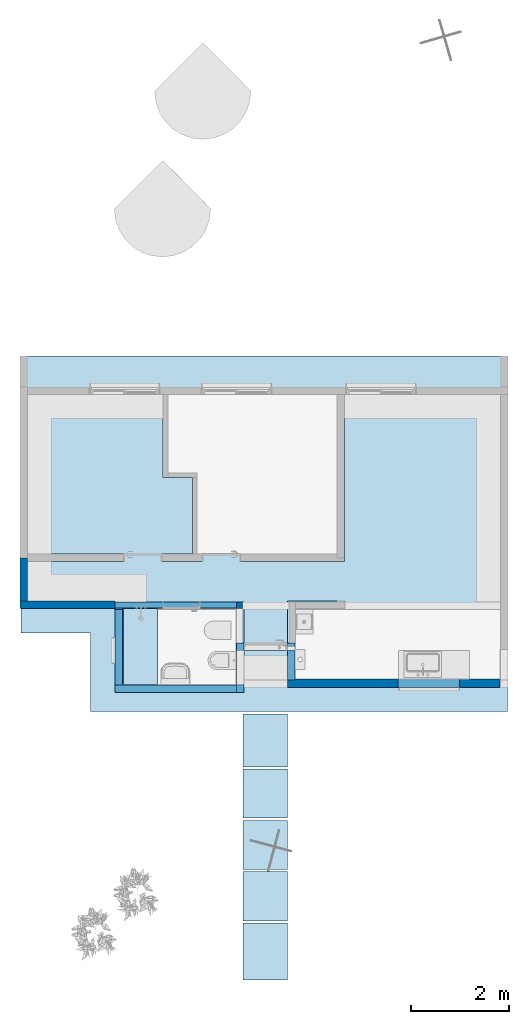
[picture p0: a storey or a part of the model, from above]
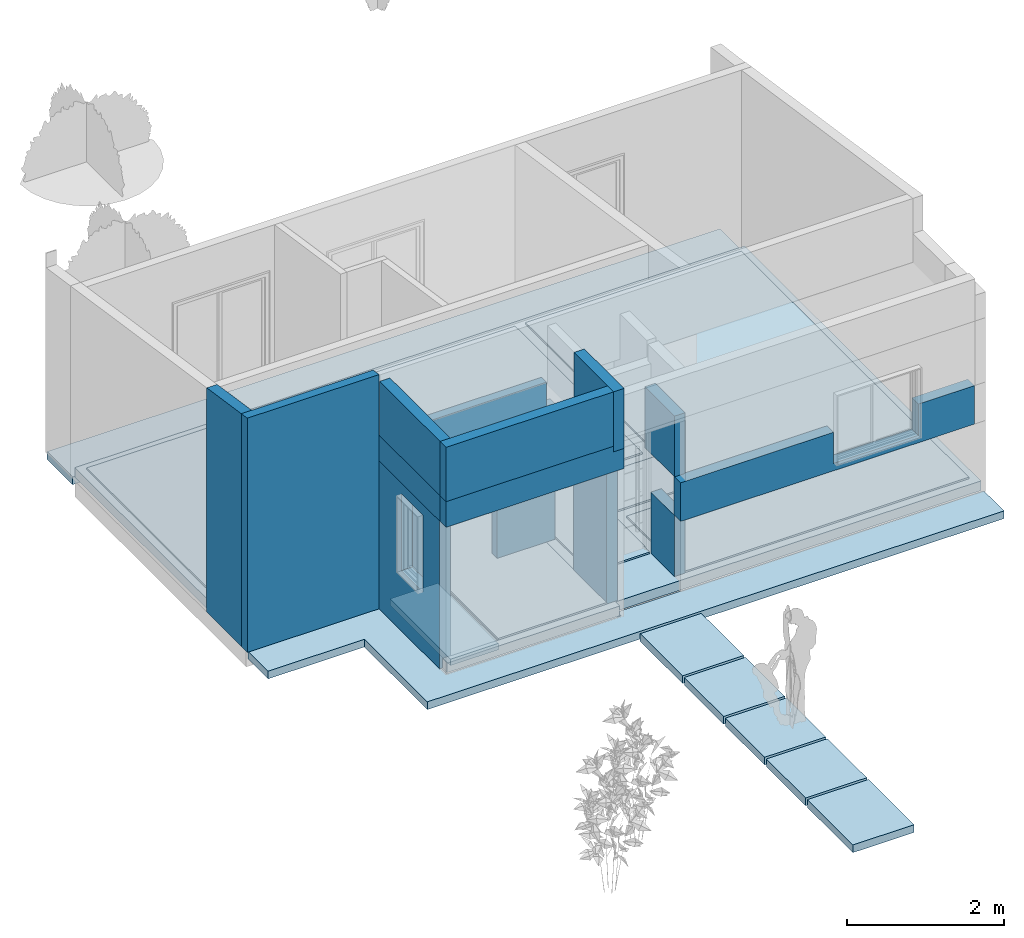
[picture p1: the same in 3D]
Properties of the parts of a building model (IFC2X3)

# File
Description: ViewDefinition [CoordinationView_V2.0]
File name: Project Number
Time: 2021-10-06T08:28:48
Written by: The EXPRESS Data Manager Version 5.02.0100.07 : 28 Aug 2013
Made in: 20200210_1400(x64) - Exporter 20.2.12.1 - Alternate UI 20.2.12.1
Comment: STEP Physical File produced by: The EXPRESS Data Manager Version 5.02.0100.07 : 28 Aug 2013 * Module: EDMstepFileFactory/EDMstandAlone * Creation date: Wed Oct 06 08:28:48 2021 * Host: d-417 * Database: C:\Users\msoler\AppData\Local\Temp\b61d57f0-5f59-4d53-9b33-197beb0c06ca\71092de3-7ad1-4322-8656-2e5e5e605928\ifc * Database version: 5507 * Database creation date: Wed Oct 06 08:28:41 2021 * Schema: IFC2X3 * Model: DataRepository.ifc * Model creation date: Wed Oct 06 08:28:42 2021 * Header model: DataRepository.ifc_HeaderModel * Header model creation date: Wed Oct 06 08:28:42 2021 * EDMuser: sdai-user * EDMgroup: sdai-group * License ID and type: 5605 : Permanent license. Expiry date: * EDMstepFileFactory options: 020000

# IfcProject, Project Number
LongName: Project Name; Phase: Project Status

# IfcSite, Surface:604594
RefLatitude: 42, 21, 31, 181945; RefLongitude: -71, -3, -24, -263305; RefElevation: 0 m
Pset_ProductRequirements - Category: Topography

# IfcBuilding
Pset_BuildingCommon - NumberOfStoreys: 2
Pset_ProductRequirements - Category: Project Information

# IfcBuildingStorey: Level:8mm Head (2)
Pset_ProductRequirements - Category: Levels
Name | LongName = Pset_AirSideSystemInformation, Name = Pset_ProductRequirements, Name | Elevation (m)
Nivel 0.0 | Nivel 0.0 | 0
Nivel 1 | Nivel 1 | 2.7

# IfcSpace (6)
In: Nivel 0.0
InteriorOrExteriorSpace: INTERNAL
Pset_ProductRequirements - Category: Rooms
Pset_SpaceCommon - Category: Rooms; FloorCovering: Cerámico; CeilingCovering: Placa yeso suspendido
Name | LongName = Pset_AirSideSystemInformation, Name = Pset_ProductRequirements, Name | Reference
1 | Hall distribuidor y paso | Hall distribuidor y paso 1
2 | Estar comedor | Estar comedor 2
4 | Dormitorio 1 | Dormitorio 1 4
5 | Dormitorio 2 | Dormitorio 2 5
6 | Baño | Baño 6 | Pset_SpaceCommon - WallCovering: cerámico
3 | Lavadero | Lavadero 3 | Pset_SpaceCommon - WallCovering: cerámico

# IfcBuildingElementProxy: Barberry - 1.0 Meters (3)
In: Nivel 0.0
Type - Pset_BuildingElementProxyCommon - Reference: Barberry - 1.0 Meters
Type - Pset_ProductRequirements - Category: Planting
Type - Pset_QuantityTakeOff - Reference: Barberry - 1.0 Meters
Pset_BuildingElementProxyCommon - sets with these values: 2
Name (M_RPC Shrub:Barberry - 1.0 Meters:...)
617424
617426
707226

# IfcBuildingElementProxy: Enscape AssetDefinition - Bamboo 5 (2)
In: Nivel 0.0
Type - Pset_BuildingElementProxyCommon - Reference: Enscape AssetDefinition - Bamboo 5
Type - Pset_ProductRequirements - Category: Planting
Type - Pset_QuantityTakeOff - Reference: Enscape AssetDefinition - Bamboo 5
Pset_BuildingElementProxyCommon - sets with these values: 2
Name (Bamboo:Enscape AssetDefinition - Bamboo 5:...)
669530
671551

# IfcBuildingElementProxy: People_01_Multiple_views_persona_01_Vistas_multiples_3530 (2)
In: Nivel 0.0
Type - Material: Sombra escala
Type - Pset_BuildingElementProxyCommon - Reference: People_01_Multiple_views_persona_01_Vistas_multiples_3530
Type - Pset_ProductRequirements - Category: Entourage
Type - Pset_QuantityTakeOff - Reference: People_01_Multiple_views_persona_01_Vistas_multiples_3530
Pset_BuildingElementProxyCommon - sets with these values: 2
Name (People_01_Multiple_views_persona_01_Vistas_multiples_3530:People_01_Multiple_views_persona_01_Vistas_multiples_3530:...)
621565
707233

# IfcBuildingElementProxy: Slab Edge:Slab Edge, Slab Edge:Slab Edge:727210
In: Nivel 0.0
Pset_BuildingElementProxyCommon - Reference: Slab Edge; sets with these values: 2
Pset_ProductRequirements - Category: Slab Edges

# IfcBuildingElementProxy: calentador solar techo inclinado, calentador solar techo inclinado:calentador solar techo inclinado:707159
In: Nivel 1
Type - Material: Aluminio, Acero inoxidable, UHMW, rojo, Laminado, marino
Type - Pset_BuildingElementProxyCommon - Reference: calentador solar techo inclinado
Type - Pset_ManufacturerTypeInformation - Manufacturer: Bicentenario Calentadores solares
Type - Pset_ProductRequirements - Category: Mechanical Equipment
Type - Pset_QuantityTakeOff - Reference: calentador solar techo inclinado
Pset_BuildingElementProxyCommon - sets with these values: 2

# IfcCovering: Compound Ceiling:1282-Aplicado de yeso (5)
Type - PredefinedType: CEILING
Type - Pset_CoveringCommon - Reference: 1282-Aplicado de yeso; TotalThickness: 0.02 m
Type - Pset_ElementShading - Roughness: 0.3048 m
Type - Pset_ProductRequirements - Category: Ceilings
Type - Pset_QuantityTakeOff - Reference: 1282-Aplicado de yeso
Material: Cielorraso aplicado de yeso 0.02 m
Name (Compound Ceiling:1282-Aplicado de yeso:...) | In
452097 | Nivel 1
452149 | Nivel 0.0
707038 | Nivel 1
707047 | 6
721033 | 4

# IfcDistributionPort (8)
Description: Flow
Name | FlowDirection
Port_707095 | SINK
Port_707095 | SOURCE
Port_707096 | SINK
2 x Port_707096 | SOURCE
Port_707125 | SINK
2 x Port_707159 | SOURCEANDSINK

# IfcDoor: P1, Puerta acceso:P1:725328
In: Nivel 0.0
Type - OperationType: SINGLE_SWING_RIGHT; ParameterTakesPrecedence: no; Sizeable: no; Material: Aluminum, Metal, Paint Finish, White, Matte
Type - Puerta acceso:P1:725328 - PanelOperation: SWINGING
OverallHeight: 2.1 m; OverallWidth: 0.85 m
Pset_DoorCommon - IsExternal: no; Reference: P1
Pset_ProductRequirements - Category: Doors
Pset_QuantityTakeOff - Reference: P1

# IfcDoor: P3 (3)
In: Nivel 0.0
Type - ParameterTakesPrecedence: no; Sizeable: no; Material: Bronce Platil, 0 - BLANCO, Pintura Esmalte Blanco Satinado
OverallHeight: 2.1 m; OverallWidth: 0.78 m
Pset_DoorCommon - IsExternal: no; Reference: P3
Pset_ProductRequirements - Category: Doors
Pset_QuantityTakeOff - Reference: P3
Name (Puerta Interior:P3:...)
707092
707093
707094

# IfcFlowTerminal: Bacha-Ferrum-Qubiq-L12K:Sin Agujero, Bacha-Ferrum-Qubiq-L12K:Sin Agujero:707125
In: 3
Material: Ceramica - Ferrum - Blanco
Pset_DistributionFlowElementCommon - Reference: Sin Agujero; sets with these values: 2
Pset_ManufacturerTypeInformation - Manufacturer: Ferrum
Pset_ProductRequirements - Category: Plumbing Fixtures

# IfcFlowTerminal: Bidet-Ferrum-Veneto-1_y_3_Agujeros:1 Agujero, Bidet-Ferrum-Veneto-1_y_3_Agujeros:1 Agujero:707096
In: Nivel 0.0
Material: Ceramica - Ferrum - Blanco
Pset_DistributionFlowElementCommon - Reference: 1 Agujero; sets with these values: 2
Pset_ManufacturerTypeInformation - Manufacturer: Ferrum
Pset_ProductRequirements - Category: Plumbing Fixtures

# IfcFlowTerminal: Cdo Ducha:Cdo Ducha, Cdo Ducha:Cdo Ducha:707099
In: 6
Material: 0 - BLANCO, Metal - Cromo pulido
Pset_DistributionFlowElementCommon - Reference: Cdo Ducha; sets with these values: 2
Pset_ProductRequirements - Category: Plumbing Fixtures

# IfcFlowTerminal: Inodoro-Ferrum-Veneto-Corto:Inodoro Corto, Inodoro-Ferrum-Veneto-Corto:Inodoro Corto:707095
In: 6
Material: Ceramica - Ferrum - Blanco
Pset_DistributionFlowElementCommon - Reference: Inodoro Corto; sets with these values: 2
Pset_ManufacturerTypeInformation - Manufacturer: Ferrum
Pset_ProductRequirements - Category: Plumbing Fixtures

# IfcFlowTerminal: Inodoro-Ferrum-Veneto-Tapa_y_Asiento:Tapa de Inodoro, Inodoro-Ferrum-Veneto-Tapa_y_Asiento:Tapa de Inodoro:707270
In: 6
Material: Plastico - Ferrum - Urea - Blanco
Pset_DistributionFlowElementCommon - Reference: Tapa de Inodoro; sets with these values: 2
Pset_ManufacturerTypeInformation - Manufacturer: Ferrum
Pset_ProductRequirements - Category: Plumbing Fixtures

# IfcFlowTerminal: Lavatorio:Lavatorio, Lavatorio:Lavatorio:707098
In: 6
Material: Porcelain
Pset_DistributionFlowElementCommon - Reference: Lavatorio; sets with these values: 2
Pset_ProductRequirements - Category: Plumbing Fixtures

# IfcFlowTerminal: M_Sink Kitchen-Single:760 x 535mm, M_Sink Kitchen-Single:760 x 535mm:707124
In: 2
Material: Steel, Polished
Pset_DistributionFlowElementCommon - Reference: 760 x 535mm; sets with these values: 2
Pset_ProductRequirements - Category: Plumbing Fixtures

# IfcFurnishingElement: EH-Esquentador a Gáz, CALEFON:EH-Esquentador a Gáz:707126
In: 3
Type - Material: Glass, EH - Preto, EH - Branco
Pset_ManufacturerTypeInformation - Manufacturer: Vulcano
Pset_ProductRequirements - Category: Casework
Pset_QuantityTakeOff - Reference: EH-Esquentador a Gáz

# IfcFurnishingElement: Mesada 1.45m, M_Counter Top w Sink:Mesada 1.45m:707123
In: 2
Type - Material: Stone
Pset_ProductRequirements - Category: Casework
Pset_QuantityTakeOff - Reference: Mesada 1.45m

# IfcOpeningElement: Opening (19)
Name | In
Basic Wall:Pi-NW-054:706999 | Nivel 0.0 | Pset_ElementShading - Roughness: 0.3048 m; Pset_ProductRequirements - Category: Walls; Pset_QuantityTakeOff - Reference: Pi-NW-054; sets with these values: 2
Floor:Platea de fundación:707003:2 | Nivel 0.0 | Pset_ElementShading - Roughness: 0.9144 m; Pset_ProductRequirements - Category: Floors; Pset_OpeningElementCommon - Reference: Platea de fundación; sets with these values: 2
Ventana batiente horizontal V2:V2:805811:1 | Nivel 0.0
M_Counter Top w Sink:Mesada 1.45m:707123:1 | 2 | Pset_ProductRequirements - Category: Casework; Pset_OpeningElementCommon - Reference: Mesada 1.45m; sets with these values: 2
Puerta acceso:P1:725328:1 | Nivel 0.0
2 x Basic Wall:Pe-NW-002:707343 | Nivel 0.0 | Pset_ElementShading - Roughness: 0.3048 m; Pset_ProductRequirements - Category: Walls; Pset_QuantityTakeOff - Reference: Pe-NW-002; sets with these values: 2
Basic Wall:Pe-NW-002:382115 | Nivel 0.0 | Pset_ElementShading - Roughness: 0.3048 m; Pset_ProductRequirements - Category: Walls; Pset_QuantityTakeOff - Reference: Pe-NW-002; sets with these values: 2
Basic Wall:Pe-NW-006:708431:1 | Nivel 0.0 | Pset_ElementShading - Roughness: 0.3048 m; Pset_ProductRequirements - Category: Walls; Pset_QuantityTakeOff - Reference: Pe-NW-006; sets with these values: 2
Puerta Interior:P3:707092:1 | Nivel 0.0
Puerta Interior:P3:707093:1 | Nivel 0.0
Puerta Interior:P3:707094:1 | Nivel 0.0
Vtana Corrediza:PV1:707120:1 | Nivel 0.0
Vtana Corrediza:PV1:707121:1 | Nivel 0.0
Vtana Corrediza:PV1:707122:1 | Nivel 0.0
Premarco metálico:Premarco metálico PV1:707163:1 | Nivel 0.0
Premarco metálico:Premarco metálico PV1:707164:1 | Nivel 0.0
Premarco metálico:Premarco metálico PV1:707165:1 | Nivel 0.0
Ventana1,20x1.20:V1:784160:1 | Nivel 0.0

# IfcRoof: Basic Roof:PC-NW-101, Basic Roof:PC-NW-101:707031
In: Nivel 1
Pset_ElementShading - Roughness: 0.9144 m
Pset_ProductRequirements - Category: Roofs
Pset_QuantityTakeOff - Reference: PC-NW-101
Pset_RoofCommon - IsExternal: yes; Reference: PC-NW-101; ProjectedArea: 51.0277 m2; TotalArea: 51.5985 m2

# IfcRoof: Basic Roof:PC-NW-102 (2)
In: Nivel 1
Pset_ElementShading - Roughness: 0.9144 m
Pset_ProductRequirements - Category: Roofs
Pset_QuantityTakeOff - Reference: PC-NW-102
Pset_RoofCommon - IsExternal: yes; Reference: PC-NW-102
Name (Basic Roof:PC-NW-102:...) | ProjectedArea (m2) = TotalArea (m2)
726101 | 3.56218
726763 | 7.48902

# IfcSlab: Basic Roof:PC-NW-101, Basic Roof:PC-NW-101:707031
In: Nivel 1
PredefinedType: ROOF; Material: Membrana asfáltica 0.004 m, OSB 0.012 m, Espuma Poliuretano Inyectado 0.095 m, OSB 0.012 m
Pset_ElementShading - Roughness: 0.9144 m
Pset_ProductRequirements - Category: Roofs
Pset_QuantityTakeOff - Reference: PC-NW-101
Pset_ReinforcementBarPitchOfSlab - Description: Cubierta inclinada Panel PSN 12; Reference: PC-NW-101
Pset_SlabCommon - IsExternal: yes; Reference: PC-NW-101; ThermalTransmittance: 0.342728 kg/K/s3; PitchAngle: 8.59437 deg

# IfcSlab: Basic Roof:PC-NW-102 (2)
In: Nivel 1
PredefinedType: ROOF; Material: Aislación térmica e hidrófuga 0.07 m, OSB 0.012 m, Poliestireno expandido 0.095 m, OSB 0.012 m
Pset_ElementShading - Roughness: 0.9144 m
Pset_ProductRequirements - Category: Roofs
Pset_QuantityTakeOff - Reference: PC-NW-102
Pset_ReinforcementBarPitchOfSlab - Description: Cubierta plana- PANEL SIP+Aislación hidrófuga+Carga pendiente+carpeta+Membrana c/aluminio; Reference: PC-NW-102
Pset_SlabCommon - PitchAngle: 0 deg; IsExternal: yes; Reference: PC-NW-102; ThermalTransmittance: 0.307767 kg/K/s3
Name (Basic Roof:PC-NW-102:...)
726101
726763

# IfcSlab: Floor:Piso Cerámico (2)
In: Nivel 0.0
Type - PredefinedType: FLOOR; Material: Ceramic Tile 0.01 m, Concrete, Sand/Cement Screed 0.015 m
Type - Pset_ElementShading - Roughness: 0.9144 m
Type - Pset_ProductRequirements - Category: Floors
Type - Pset_QuantityTakeOff - Reference: Piso Cerámico
Type - Pset_ReinforcementBarPitchOfSlab - Description: Receptáculo baño; Reference: Piso Cerámico
Type - Pset_SlabCommon - IsExternal: no; Reference: Piso Cerámico; ThermalTransmittance: 44.104 kg/K/s3
Pset_SlabCommon - LoadBearing: no; PitchAngle: 0 deg
Name (Floor:Piso Cerámico:...)
707053
707115

# IfcSlab: Floor:Platea de fundación, Floor:Platea de fundación:707003
In: Nivel 0.0
Type - PredefinedType: FLOOR; Material: Concrete, Cast In Situ 0.15 m
Type - Pset_ElementShading - Roughness: 0.9144 m
Type - Pset_ProductRequirements - Category: Floors
Type - Pset_QuantityTakeOff - Reference: Platea de fundación
Type - Pset_ReinforcementBarPitchOfSlab - Description: Platea de fundación; Reference: Platea de fundación
Type - Pset_SlabCommon - IsExternal: no; Reference: Platea de fundación; ThermalTransmittance: 6.97333 kg/K/s3
Pset_SlabCommon - LoadBearing: no; PitchAngle: 0 deg

# IfcSlab: Floor:Platea de fundación, receptaculo baño, Floor:Platea de fundación, receptaculo baño:707108
In: Nivel 0.0
Type - PredefinedType: FLOOR; Material: Concrete, Cast In Situ 0.1 m
Type - Pset_ElementShading - Roughness: 0.9144 m
Type - Pset_ProductRequirements - Category: Floors
Type - Pset_QuantityTakeOff - Reference: Platea de fundación, receptaculo baño
Type - Pset_ReinforcementBarPitchOfSlab - Description: Receptáculo baño; Reference: Platea de fundación, receptaculo baño
Type - Pset_SlabCommon - IsExternal: no; Reference: Platea de fundación, receptaculo baño; ThermalTransmittance: 10.46 kg/K/s3
Pset_SlabCommon - LoadBearing: no; PitchAngle: 0 deg

# IfcSlab: Floor:Vereda de acceso, Floor:Vereda de acceso:705603:5
In: Nivel 0.0
Type - PredefinedType: FLOOR; Material: Hormigón Armado veredines 0.12 m
Type - Pset_ElementShading - Roughness: 0.9144 m
Type - Pset_ProductRequirements - Category: Floors
Type - Pset_QuantityTakeOff - Reference: Vereda de acceso
Type - Pset_ReinforcementBarPitchOfSlab - Description: Vereda de acceso; Reference: Vereda de acceso
Type - Pset_SlabCommon - Reference: Vereda de acceso; IsExternal: no; ThermalTransmittance: 8.71667 kg/K/s3
Pset_SlabCommon - LoadBearing: no; PitchAngle: 0 deg

# IfcSlab: Floor:Vereda de acceso (4)
In: Nivel 0.0
Type - PredefinedType: FLOOR
Type - Pset_ElementShading - Roughness: 0.9144 m
Type - Pset_ProductRequirements - Category: Floors
Type - Pset_QuantityTakeOff - Reference: Vereda de acceso
Type - Pset_ReinforcementBarPitchOfSlab - Description: Vereda de acceso; Reference: Vereda de acceso
Type - Pset_SlabCommon - Reference: Vereda de acceso; IsExternal: no; ThermalTransmittance: 8.71667 kg/K/s3
Material: Hormigón Armado veredines 0.12 m
Pset_SlabCommon - LoadBearing: no; PitchAngle: 0 deg
Name (Floor:Vereda de acceso:...)
705603
705603:2
705603:3
705603:4

# IfcSlab: Floor:Veredín perimetral, Floor:Veredín perimetral:707015:2
In: Nivel 0.0
Type - PredefinedType: FLOOR; Material: Hormigón Armado veredines 0.12 m
Type - Pset_ElementShading - Roughness: 0.9144 m
Type - Pset_ProductRequirements - Category: Floors
Type - Pset_QuantityTakeOff - Reference: Veredín perimetral
Type - Pset_ReinforcementBarPitchOfSlab - Description: Veredín perimetral; Reference: Veredín perimetral
Type - Pset_SlabCommon - IsExternal: no; Reference: Veredín perimetral; ThermalTransmittance: 8.71667 kg/K/s3
Pset_SlabCommon - LoadBearing: no; PitchAngle: 0 deg

# IfcSlab: Floor:Veredín perimetral, Floor:Veredín perimetral:707015
In: Nivel 0.0
Type - PredefinedType: FLOOR
Type - Pset_ElementShading - Roughness: 0.9144 m
Type - Pset_ProductRequirements - Category: Floors
Type - Pset_QuantityTakeOff - Reference: Veredín perimetral
Type - Pset_ReinforcementBarPitchOfSlab - Description: Veredín perimetral; Reference: Veredín perimetral
Type - Pset_SlabCommon - IsExternal: no; Reference: Veredín perimetral; ThermalTransmittance: 8.71667 kg/K/s3
Material: Hormigón Armado veredines 0.12 m
Pset_SlabCommon - LoadBearing: no; PitchAngle: 0 deg

# IfcWall: Basic Wall:Pe-NW-002 (3)
In: Nivel 0.0
Type - PredefinedType: STANDARD; Material: Placa cementicia 0.0125 m, Bastidor metálico 0.03 m, OSB 0.011 m, Poliestireno expandido 0.046 m, OSB 0.011 m, Bastidor metálico 0.03 m, Placa roca de Yeso 12,5mm 0.0125 m
Type - Pset_ElementShading - Roughness: 0.3048 m
Type - Pset_ProductRequirements - Category: Walls
Type - Pset_QuantityTakeOff - Reference: Pe-NW-002
Type - Pset_ReinforcementBarPitchOfWall - Description: Pe-p.cem+SIP+p.yeso; Reference: Pe-NW-002
Type - Pset_WallCommon - IsExternal: no; Reference: Pe-NW-002; ThermalTransmittance: 0.255783 kg/K/s3
Pset_WallCommon - LoadBearing: no; IsExternal: yes
Name (Basic Wall:Pe-NW-002:...) | ExtendToStructure
706994 | yes
724492 | yes
802347 | no

# IfcWall: Basic Wall:Pe-NW-006, Basic Wall:Pe-NW-006:707314
In: Nivel 0.0
Type - PredefinedType: STANDARD; Material: Revestimiento exterior tipo siding 0.012 m, Bastidor metálico 0.03 m, OSB 0.011 m, Poliestireno expandido 0.046 m, OSB 0.011 m, Bastidor metálico 0.03 m, Placa roca de Yeso 12,5mm 0.012 m, Revestimiento Cerámico muro 0.012 m
Type - Pset_ElementShading - Roughness: 0.3048 m
Type - Pset_ProductRequirements - Category: Walls
Type - Pset_QuantityTakeOff - Reference: Pe-NW-006
Type - Pset_ReinforcementBarPitchOfWall - Description: Pe-revert.ext+SIP+p.yeso+rev. cerámico; Reference: Pe-NW-006
Type - Pset_WallCommon - IsExternal: no; Reference: Pe-NW-006; ThermalTransmittance: 0.249525 kg/K/s3
Material: Revestimiento exterior tipo siding, Bastidor metálico (2), OSB (2), Poliestireno expandido, Placa roca de Yeso 12,5mm, Revestimiento Cerámico muro
Pset_WallCommon - LoadBearing: no; IsExternal: yes; ExtendToStructure: no

# IfcWallStandardCase: Basic Wall:Pe-NW-001 (6)
In: Nivel 0.0
Type - PredefinedType: STANDARD; Material: Placa cementicia 0.0125 m, Bastidor metálico 0.03 m, OSB 0.011 m, Poliestireno expandido 0.046 m, OSB 0.011 m, Bastidor metálico 0.03 m, Placa cementicia 0.012 m
Type - Pset_ElementShading - Roughness: 0.3048 m
Type - Pset_ProductRequirements - Category: Walls
Type - Pset_QuantityTakeOff - Reference: Pe-NW-001
Type - Pset_ReinforcementBarPitchOfWall - Description: Pe-p.cem+SIP+p.cem; Reference: Pe-NW-001
Type - Pset_WallCommon - IsExternal: no; Reference: Pe-NW-001; ThermalTransmittance: 0.255034 kg/K/s3
Pset_WallCommon - LoadBearing: no; IsExternal: yes
Name (Basic Wall:Pe-NW-001:...) | ExtendToStructure
706985 | yes
707091 | no
707344 | no
708804 | no
724327 | no
727087 | no

# IfcWallStandardCase: Basic Wall:Pe-NW-002 (9)
In: Nivel 0.0
Type - PredefinedType: STANDARD; Material: Placa cementicia 0.0125 m, Bastidor metálico 0.03 m, OSB 0.011 m, Poliestireno expandido 0.046 m, OSB 0.011 m, Bastidor metálico 0.03 m, Placa roca de Yeso 12,5mm 0.0125 m
Type - Pset_ElementShading - Roughness: 0.3048 m
Type - Pset_ProductRequirements - Category: Walls
Type - Pset_QuantityTakeOff - Reference: Pe-NW-002
Type - Pset_ReinforcementBarPitchOfWall - Description: Pe-p.cem+SIP+p.yeso; Reference: Pe-NW-002
Type - Pset_WallCommon - IsExternal: no; Reference: Pe-NW-002; ThermalTransmittance: 0.255783 kg/K/s3
Pset_WallCommon - LoadBearing: no; IsExternal: yes
Name (Basic Wall:Pe-NW-002:...) | ExtendToStructure
706986 | yes
707189 | yes
707336 | no
707343 | no
708803 | no
725217 | no
799828 | yes
802344 | no
802350 | no

# IfcWallStandardCase: Basic Wall:Pe-NW-003 (3)
In: Nivel 0.0
Type - PredefinedType: STANDARD; Material: Placa cementicia 0.0125 m, Bastidor metálico 0.03 m, OSB 0.011 m, Poliestireno expandido 0.046 m, OSB 0.011 m, Bastidor metálico 0.03 m, Placa roca de Yeso 12,5mm 0.012 m, Revestimiento Cerámico muro 0.012 m
Type - Pset_ElementShading - Roughness: 0.3048 m
Type - Pset_ProductRequirements - Category: Walls
Type - Pset_QuantityTakeOff - Reference: Pe-NW-003
Type - Pset_ReinforcementBarPitchOfWall - Description: Pe-p.cem+SIP+p.yeso+rev.cerámico; Reference: Pe-NW-003
Type - Pset_WallCommon - IsExternal: no; Reference: Pe-NW-003; ThermalTransmittance: 0.25513 kg/K/s3
Pset_WallCommon - LoadBearing: no; IsExternal: yes; ExtendToStructure: no
Name (Basic Wall:Pe-NW-003:...)
707335
707342
708802

# IfcWallStandardCase: Basic Wall:Pe-NW-004 (3)
In: Nivel 0.0
Type - PredefinedType: STANDARD; Material: Revestimiento exterior tipo siding 0.012 m, Bastidor metálico 0.03 m, OSB 0.011 m, Poliestireno expandido 0.046 m, OSB 0.011 m, Bastidor metálico 0.03 m, Placa cementicia 0.012 m
Type - Pset_ElementShading - Roughness: 0.3048 m
Type - Pset_ProductRequirements - Category: Walls
Type - Pset_QuantityTakeOff - Reference: Pe-NW-004
Type - Pset_ReinforcementBarPitchOfWall - Description: Pe-revest.ext+p.cem+SIP+p.cem; Reference: Pe-NW-004
Type - Pset_WallCommon - IsExternal: no; Reference: Pe-NW-004; ThermalTransmittance: 0.249433 kg/K/s3
Pset_WallCommon - LoadBearing: no; IsExternal: yes; ExtendToStructure: no
Name (Basic Wall:Pe-NW-004:...)
707316
708433
807296

# IfcWallStandardCase: Basic Wall:Pe-NW-005 (3)
In: Nivel 0.0
Type - PredefinedType: STANDARD; Material: Revestimiento exterior tipo siding 0.012 m, Bastidor metálico 0.03 m, OSB 0.011 m, Poliestireno expandido 0.046 m, OSB 0.011 m, Bastidor metálico 0.03 m, Placa roca de Yeso 12,5mm 0.012 m
Type - Pset_ElementShading - Roughness: 0.3048 m
Type - Pset_ProductRequirements - Category: Walls
Type - Pset_QuantityTakeOff - Reference: Pe-NW-005
Type - Pset_ReinforcementBarPitchOfWall - Description: Pe-revest.ext+p.cem+SIP+p.yeso; Reference: Pe-NW-005
Type - Pset_WallCommon - IsExternal: no; Reference: Pe-NW-005; ThermalTransmittance: 0.250149 kg/K/s3
Pset_WallCommon - LoadBearing: no; IsExternal: yes; ExtendToStructure: no
Name (Basic Wall:Pe-NW-005:...)
800984
800985
807295

# IfcWallStandardCase: Basic Wall:Pe-NW-006 (2)
In: Nivel 0.0
Type - PredefinedType: STANDARD; Material: Revestimiento exterior tipo siding 0.012 m, Bastidor metálico 0.03 m, OSB 0.011 m, Poliestireno expandido 0.046 m, OSB 0.011 m, Bastidor metálico 0.03 m, Placa roca de Yeso 12,5mm 0.012 m, Revestimiento Cerámico muro 0.012 m
Type - Pset_ElementShading - Roughness: 0.3048 m
Type - Pset_ProductRequirements - Category: Walls
Type - Pset_QuantityTakeOff - Reference: Pe-NW-006
Type - Pset_ReinforcementBarPitchOfWall - Description: Pe-revert.ext+SIP+p.yeso+rev. cerámico; Reference: Pe-NW-006
Type - Pset_WallCommon - IsExternal: no; Reference: Pe-NW-006; ThermalTransmittance: 0.249525 kg/K/s3
Pset_WallCommon - LoadBearing: no; IsExternal: yes; ExtendToStructure: no
Name (Basic Wall:Pe-NW-006:...)
708431
807294

# IfcWallStandardCase: Basic Wall:Pi-NW-050 (3)
In: Nivel 0.0
Type - PredefinedType: STANDARD; Material: Placa roca de Yeso 12,5mm 0.0125 m, OSB 0.012 m, Poliestireno expandido 0.046 m, OSB 0.012 m, Placa roca de Yeso 12,5mm 0.012 m
Type - Pset_ElementShading - Roughness: 0.3048 m
Type - Pset_ProductRequirements - Category: Walls
Type - Pset_QuantityTakeOff - Reference: Pi-NW-050
Type - Pset_ReinforcementBarPitchOfWall - Description: Pi-p.yeso+SIP+ p.yeso; Reference: Pi-NW-050
Type - Pset_WallCommon - IsExternal: no; Reference: Pi-NW-050; ThermalTransmittance: 0.660377 kg/K/s3
Pset_WallCommon - LoadBearing: no; IsExternal: yes; ExtendToStructure: yes
Name (Basic Wall:Pi-NW-050:...)
706995
706996
706997

# IfcWallStandardCase: Basic Wall:Pi-NW-052 (2)
In: Nivel 0.0
Type - PredefinedType: STANDARD; Material: Placa roca de Yeso 12,5mm 0.0125 m, OSB 0.012 m, Poliestireno expandido 0.046 m, OSB 0.012 m, Bastidor metálico 0.03 m, Placa roca de Yeso 12,5mm 0.012 m
Type - Pset_ElementShading - Roughness: 0.3048 m
Type - Pset_ProductRequirements - Category: Walls
Type - Pset_QuantityTakeOff - Reference: Pi-NW-052
Type - Pset_ReinforcementBarPitchOfWall - Description: Pi-p.yeso+SIP+bastidor+ p.yeso; Reference: Pi-NW-052
Type - Pset_WallCommon - IsExternal: no; Reference: Pi-NW-052; ThermalTransmittance: 0.368421 kg/K/s3
Pset_WallCommon - LoadBearing: no; IsExternal: yes; ExtendToStructure: no
Name (Basic Wall:Pi-NW-052:...)
799644
799671

# IfcWallStandardCase: Basic Wall:Pi-NW-053 (4)
In: Nivel 0.0
Type - PredefinedType: STANDARD; Material: Placa roca de Yeso 12,5mm 0.0125 m, OSB 0.012 m, Poliestireno expandido 0.046 m, OSB 0.012 m, Bastidor metálico 0.03 m, Placa roca de Yeso 12,5mm 0.012 m, Revestimiento Cerámico muro 0.012 m
Type - Pset_ElementShading - Roughness: 0.3048 m
Type - Pset_ProductRequirements - Category: Walls
Type - Pset_QuantityTakeOff - Reference: Pi-NW-053
Type - Pset_ReinforcementBarPitchOfWall - Description: Pi-p.yeso+SIP+bastidor+p.yeso+rev cerámico; Reference: Pi-NW-053
Type - Pset_WallCommon - IsExternal: no; Reference: Pi-NW-053; ThermalTransmittance: 0.367069 kg/K/s3
Pset_WallCommon - LoadBearing: no; IsExternal: yes; ExtendToStructure: no
Name (Basic Wall:Pi-NW-053:...)
709278
715013
718437
799645

# IfcWallStandardCase: Basic Wall:Pi-NW-054 (2)
In: Nivel 0.0
Type - PredefinedType: STANDARD; Material: Placa roca de Yeso 12,5mm 0.0125 m, Bastidor metálico 0.03 m, OSB 0.012 m, Poliestireno expandido 0.046 m, OSB 0.012 m, Bastidor metálico 0.03 m, Placa roca de Yeso 12,5mm 0.012 m
Type - Pset_ElementShading - Roughness: 0.3048 m
Type - Pset_ProductRequirements - Category: Walls
Type - Pset_QuantityTakeOff - Reference: Pi-NW-054
Type - Pset_ReinforcementBarPitchOfWall - Description: Pi-p.yeso+SIP+bastidor+ p.yeso; Reference: Pi-NW-054
Type - Pset_WallCommon - IsExternal: no; Reference: Pi-NW-054; ThermalTransmittance: 0.255474 kg/K/s3
Pset_WallCommon - LoadBearing: no; IsExternal: yes; ExtendToStructure: yes
Name (Basic Wall:Pi-NW-054:...)
706998
706999

# IfcWindow: PV1 (3)
In: Nivel 0.0
Type - ParameterTakesPrecedence: no; Sizeable: no; Material: Glass, Laminate, White
OverallHeight: 2.1 m; OverallWidth: 1.4 m
Pset_ProductRequirements - Category: Windows
Pset_QuantityTakeOff - Reference: PV1
Pset_WindowCommon - IsExternal: yes; Reference: PV1
Name (Vtana Corrediza:PV1:...)
707120
707121
707122

# IfcWindow: Premarco metálico PV1 (3)
In: Nivel 0.0
Type - ParameterTakesPrecedence: no; Sizeable: no; Material: Chapa plegada
OverallHeight: 2.13 m; OverallWidth: 1.44 m
Pset_ProductRequirements - Category: Windows
Pset_QuantityTakeOff - Reference: Premarco metálico PV1
Pset_WindowCommon - IsExternal: yes; Reference: Premarco metálico PV1
Name (Premarco metálico:Premarco metálico PV1:...)
707163
707164
707165

# IfcWindow: V1, Ventana1,20x1.20:V1:784160
In: Nivel 0.0
Type - ConstructionType: OTHER_CONSTRUCTION; OperationType: DOUBLE_PANEL_VERTICAL; ParameterTakesPrecedence: no; Sizeable: no; Classification: B2020100 Windows (Uniformat); Material: Chapa plegada, NBS_Concept, NBS_Glass_Double
OverallHeight: 1.1 m; OverallWidth: 1.25 m
Pset_DoorWindowGlazingType - GlassLayers: 0; FillGas: n/a; GlassColor: n/a; IsTempered: no; IsLaminated: no; IsCoated: no; IsWired: no; Translucency: 0; Reflectivity: 0; BeamRadiationTransmittance: 0; SolarHeatGainTransmittance: 0; ThermalTransmittanceSummer: 0 kg/K/s3; ThermalTransmittanceWinter: 0 kg/K/s3
Pset_ElementShading - Color: n/a
Pset_ManufacturerOccurrence - BarCode: n/a; SerialNumber: n/a
Pset_ManufacturerTypeInformation - ModelReference: Double window with side hung opening lights; Manufacturer: n/a
Pset_ProductRequirements - Name: ExternalWindowSystem_Double_SideHungLight-SideHungLight; Category: Windows
Pset_QuantityTakeOff - Reference: n/a
Pset_WindowCommon - IsExternal: no; Reference: n/a; FireRating: n/a; AcousticRating: n/a; SecurityRating: n/a; Infiltration: 0 m3/s; ThermalTransmittance: 0 kg/K/s3; GlazingAreaFraction: 0; SmokeStop: no

# IfcWindow: V2, Ventana batiente horizontal V2:V2:805811
In: Nivel 0.0
Type - ParameterTakesPrecedence: no; Sizeable: no; Material: Chapa plegada, Glass, Aluminum
OverallHeight: 1.2 m; OverallWidth: 0.55 m
Pset_ProductRequirements - Category: Windows
Pset_QuantityTakeOff - Reference: V2
Pset_WindowCommon - IsExternal: yes; Reference: V2
